VERSION 5.6 ;
BUSBITCHARS "[]" ;
DIVIDERCHAR "/" ;

# Signal pins on the left edge only: pin-aware halos pad that side alone.
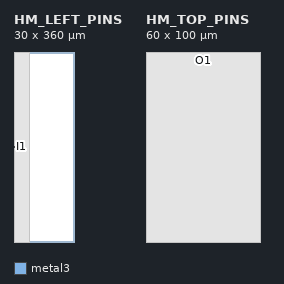
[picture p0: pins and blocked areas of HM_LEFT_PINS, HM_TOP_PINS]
MACRO HM_LEFT_PINS
  CLASS BLOCK ;
  FOREIGN HM_LEFT_PINS 0 0 ;
  ORIGIN 0 0 ;
  SYMMETRY X Y ;
  SIZE 30 BY 360 ;
  PIN I1
    DIRECTION INPUT ;
    PORT
      LAYER metal3 ;
        RECT 0 180 0.140 180.070 ;
    END
  END I1
  OBS
      LAYER metal3 ;
        RECT 0 0 30 360 ;
  END
END HM_LEFT_PINS

# Signal pins on the top edge only.
MACRO HM_TOP_PINS
  CLASS BLOCK ;
  FOREIGN HM_TOP_PINS 0 0 ;
  ORIGIN 0 0 ;
  SYMMETRY X Y ;
  SIZE 60 BY 100 ;
  PIN O1
    DIRECTION OUTPUT ;
    PORT
      LAYER metal3 ;
        RECT 30 99.930 30.140 100 ;
    END
  END O1
  OBS
      LAYER metal3 ;
        RECT 0 0 60 100 ;
  END
END HM_TOP_PINS

END LIBRARY
